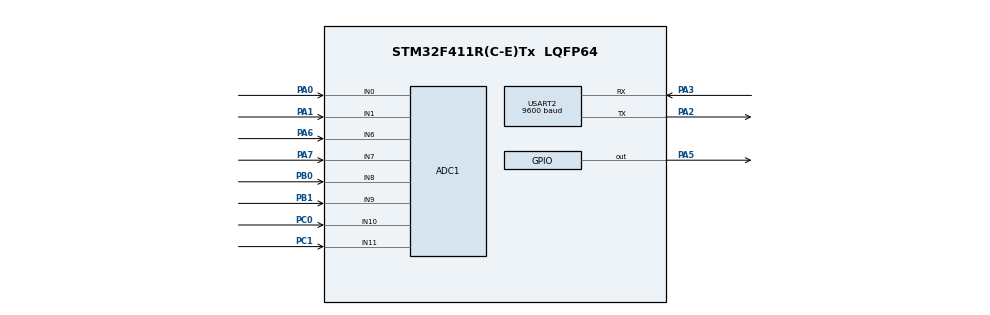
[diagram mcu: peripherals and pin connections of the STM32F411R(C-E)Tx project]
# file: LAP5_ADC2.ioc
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ADC1.Channel-13\#ChannelRegularConversion=ADC_CHANNEL_0
ADC1.Channel-14\#ChannelRegularConversion=ADC_CHANNEL_1
ADC1.Channel-15\#ChannelRegularConversion=ADC_CHANNEL_6
ADC1.Channel-16\#ChannelRegularConversion=ADC_CHANNEL_7
ADC1.Channel-17\#ChannelRegularConversion=ADC_CHANNEL_8
ADC1.Channel-18\#ChannelRegularConversion=ADC_CHANNEL_9
ADC1.Channel-19\#ChannelRegularConversion=ADC_CHANNEL_10
ADC1.Channel-20\#ChannelRegularConversion=ADC_CHANNEL_11
ADC1.ContinuousConvMode=ENABLE
ADC1.DMAContinuousRequests=ENABLE
ADC1.NbrOfConversion=8
ADC1.NbrOfConversionFlag=1
ADC1.Rank-13\#ChannelRegularConversion=1
ADC1.Rank-14\#ChannelRegularConversion=2
ADC1.Rank-15\#ChannelRegularConversion=3
ADC1.Rank-16\#ChannelRegularConversion=4
ADC1.Rank-17\#ChannelRegularConversion=5
ADC1.Rank-18\#ChannelRegularConversion=6
ADC1.Rank-19\#ChannelRegularConversion=7
ADC1.Rank-20\#ChannelRegularConversion=8
ADC1.SamplingTime-13\#ChannelRegularConversion=ADC_SAMPLETIME_3CYCLES
ADC1.SamplingTime-14\#ChannelRegularConversion=ADC_SAMPLETIME_3CYCLES
ADC1.SamplingTime-15\#ChannelRegularConversion=ADC_SAMPLETIME_3CYCLES
ADC1.SamplingTime-16\#ChannelRegularConversion=ADC_SAMPLETIME_3CYCLES
ADC1.SamplingTime-17\#ChannelRegularConversion=ADC_SAMPLETIME_3CYCLES
ADC1.SamplingTime-18\#ChannelRegularConversion=ADC_SAMPLETIME_3CYCLES
ADC1.SamplingTime-19\#ChannelRegularConversion=ADC_SAMPLETIME_3CYCLES
ADC1.SamplingTime-20\#ChannelRegularConversion=ADC_SAMPLETIME_3CYCLES
ADC1.master=1
Dma.ADC1.0.Direction=DMA_PERIPH_TO_MEMORY
Dma.ADC1.0.FIFOMode=DMA_FIFOMODE_DISABLE
Dma.ADC1.0.Instance=DMA2_Stream0
Dma.ADC1.0.MemDataAlignment=DMA_MDATAALIGN_WORD
Dma.ADC1.0.MemInc=DMA_MINC_ENABLE
Dma.ADC1.0.Mode=DMA_CIRCULAR
Dma.ADC1.0.PeriphDataAlignment=DMA_PDATAALIGN_WORD
Dma.ADC1.0.PeriphInc=DMA_PINC_DISABLE
Dma.ADC1.0.Priority=DMA_PRIORITY_LOW
Dma.Request0=ADC1
Mcu.Family=STM32F4
Mcu.Name=STM32F411R(C-E)Tx
Mcu.Package=LQFP64
NVIC.DMA2_Stream0_IRQn=true\:0\:0\:false\:false\:true\:false\:true
NVIC.PriorityGroup=NVIC_PRIORITYGROUP_2
PA0-WKUP.Signal=ADCx_IN0
PA1.Signal=ADCx_IN1
PA2.Mode=Asynchronous
PA2.Signal=USART2_TX
PA3.Mode=Asynchronous
PA3.Signal=USART2_RX
PA5.Signal=GPIO_Output
PA6.Signal=ADCx_IN6
PA7.Signal=ADCx_IN7
PB0.Signal=ADCx_IN8
PB1.Signal=ADCx_IN9
PC0.Signal=ADCx_IN10
PC1.Signal=ADCx_IN11
ProjectManager.HeapSize=0x200
ProjectManager.StackSize=0x400
ProjectManager.TargetToolchain=MDK-ARM V5.27
RCC.48MHZClocksFreq_Value=38400000
RCC.AHBCLKDivider=RCC_SYSCLK_DIV16
RCC.AHBFreq_Value=4800000
RCC.APB1CLKDivider=RCC_HCLK_DIV2
RCC.APB1Freq_Value=2400000
RCC.APB1TimFreq_Value=4800000
RCC.APB2Freq_Value=4800000
RCC.APB2TimFreq_Value=4800000
RCC.CortexFreq_Value=600000
RCC.Cortex_Div=SYSTICK_CLKSOURCE_HCLK_DIV8
RCC.FLatency-AdvancedSettings=FLASH_LATENCY_0
RCC.HCLKFreq_Value=4800000
RCC.HSE_VALUE=8000000
RCC.HSI_VALUE=16000000
RCC.LSE_VALUE=32768
RCC.PLLM=10
RCC.PLLN=96
RCC.SYSCLKFreq_VALUE=76800000
RCC.SYSCLKSource=RCC_SYSCLKSOURCE_PLLCLK
RCC.VCOOutputFreq_Value=153600000
SH.ADCx_IN0.0=ADC1_IN0,IN0
SH.ADCx_IN1.0=ADC1_IN1,IN1
SH.ADCx_IN10.0=ADC1_IN10,IN10
SH.ADCx_IN11.0=ADC1_IN11,IN11
SH.ADCx_IN6.0=ADC1_IN6,IN6
SH.ADCx_IN7.0=ADC1_IN7,IN7
SH.ADCx_IN8.0=ADC1_IN8,IN8
SH.ADCx_IN9.0=ADC1_IN9,IN9
USART2.BaudRate=9600
USART2.VirtualMode=VM_ASYNC
board=NUCLEO-F411RE

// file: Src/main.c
/* USER CODE BEGIN Header */
/**
  ******************************************************************************
  * @file           : main.c
  * @brief          : Main program body
  ******************************************************************************
  * @attention
  *
  * <h2><center>&copy; Copyright (c) 2020 STMicroelectronics.
  * All rights reserved.</center></h2>
  *
  * This software component is licensed by ST under BSD 3-Clause license,
  * the "License"; You may not use this file except in compliance with the
  * License. You may obtain a copy of the License at:
  *                        opensource.org/licenses/BSD-3-Clause
  *
  ******************************************************************************
  */
/* USER CODE END Header */

#include "main.h"
#include "adc.h"
#include "dma.h"
#include "usart.h"
#include "gpio.h"

/* USER CODE BEGIN Includes */
#include "string.h"
#include "stdio.h"
#include "stdbool.h"
/* USER CODE END Includes */

/* USER CODE BEGIN PV */
uint32_t adc_val[8];
char str[20];
char str2[20];
bool readpin;
/* USER CODE END PV */

void SystemClock_Config(void);
/* USER CODE BEGIN PFP */
void displayValue(uint32_t, int ,char str2[]);
void uart_send_msg(char str[]);
/* USER CODE END PFP */

int main(void)
{

  /* MCU Configuration--------------------------------------------------------*/

  /* Reset of all peripherals, Initializes the Flash interface and the Systick. */
  HAL_Init();

  /* Configure the system clock */
  SystemClock_Config();

  /* Initialize all configured peripherals */
  MX_GPIO_Init();
  MX_DMA_Init();
  MX_ADC1_Init();
  MX_USART2_UART_Init();
  /* USER CODE BEGIN 2 */
	HAL_ADC_Start_DMA(&hadc1, adc_val, 8);
  /* USER CODE END 2 */

  /* Infinite loop */
  while (1)
  {

    /* USER CODE BEGIN 3 */
		displayValue(adc_val[0], 0,"v LDR");
		HAL_Delay(125);
		displayValue(adc_val[1], 1,"v LDR");
		HAL_Delay(125);
		displayValue(adc_val[2], 2,"v LDR");
		HAL_Delay(125);
		displayValue(adc_val[3], 3,"v Potentiometer");
		HAL_Delay(125);
		displayValue(adc_val[4], 4,"v Potentiometer");
		HAL_Delay(125);
		displayValue(adc_val[5], 5,"v Potentiometer");
		HAL_Delay(125);
		displayValue(adc_val[6], 6,"v Potentiometer");
		HAL_Delay(125);
		displayValue(adc_val[7], 7,"v LDR");
		HAL_Delay(125);
  }
  /* USER CODE END 3 */
}

void SystemClock_Config(void)
{
  RCC_OscInitTypeDef RCC_OscInitStruct = {0};
  RCC_ClkInitTypeDef RCC_ClkInitStruct = {0};

  /** Configure the main internal regulator output voltage
  */
  __HAL_RCC_PWR_CLK_ENABLE();
  __HAL_PWR_VOLTAGESCALING_CONFIG(PWR_REGULATOR_VOLTAGE_SCALE1);
  /** Initializes the CPU, AHB and APB busses clocks
  */
  RCC_OscInitStruct.OscillatorType = RCC_OSCILLATORTYPE_HSI;
  RCC_OscInitStruct.HSIState = RCC_HSI_ON;
  RCC_OscInitStruct.HSICalibrationValue = RCC_HSICALIBRATION_DEFAULT;
  RCC_OscInitStruct.PLL.PLLState = RCC_PLL_ON;
  RCC_OscInitStruct.PLL.PLLSource = RCC_PLLSOURCE_HSI;
  RCC_OscInitStruct.PLL.PLLM = 8;
  RCC_OscInitStruct.PLL.PLLN = 100;
  RCC_OscInitStruct.PLL.PLLP = RCC_PLLP_DIV2;
  RCC_OscInitStruct.PLL.PLLQ = 4;
  if (HAL_RCC_OscConfig(&RCC_OscInitStruct) != HAL_OK)
  {
    Error_Handler();
  }
  /** Initializes the CPU, AHB and APB busses clocks
  */
  RCC_ClkInitStruct.ClockType = RCC_CLOCKTYPE_HCLK|RCC_CLOCKTYPE_SYSCLK
                              |RCC_CLOCKTYPE_PCLK1|RCC_CLOCKTYPE_PCLK2;
  RCC_ClkInitStruct.SYSCLKSource = RCC_SYSCLKSOURCE_PLLCLK;
  RCC_ClkInitStruct.AHBCLKDivider = RCC_SYSCLK_DIV1;
  RCC_ClkInitStruct.APB1CLKDivider = RCC_HCLK_DIV2;
  RCC_ClkInitStruct.APB2CLKDivider = RCC_HCLK_DIV1;

  if (HAL_RCC_ClockConfig(&RCC_ClkInitStruct, FLASH_LATENCY_3) != HAL_OK)
  {
    Error_Handler();
  }
}

/* USER CODE BEGIN 4 */
void displayValue(uint32_t adc_val, int i,char str2[])
{
	char vin[10],si[4];
	float voltage = (adc_val*3.3)/4096;
	sprintf(str, "Ox%010X", adc_val);
	sprintf(vin, "%.2f", voltage);
	sprintf(si,"%i",i);
	HAL_UART_Transmit(&huart2, (uint8_t*)"adc_channel ", 12,1000);
	HAL_UART_Transmit(&huart2, (uint8_t*)si, strlen(si), 1000);
	HAL_UART_Transmit(&huart2, (uint8_t*)" => ", 4,1000);
	HAL_UART_Transmit(&huart2, (uint8_t*)str, strlen(str),1000);
	HAL_UART_Transmit(&huart2, (uint8_t*)" vin => ", 8,1000);
	HAL_UART_Transmit(&huart2, (uint8_t*)vin, strlen(vin),1000);
	HAL_UART_Transmit(&huart2, (uint8_t*)str2, strlen(str2),1000);
	HAL_UART_Transmit(&huart2, (uint8_t*)"\n\r", 4,1000);

	// uart_send_msg(str);
	// uart_send_msg(&vin);
}
void HAL_ADC_ConvHalfCpltCallback(ADC_HandleTypeDef* hadc1)
{
	//HAL_UART_Transmit(&huart2, (uint8_t*)"HALF", 4, 100);
	HAL_GPIO_WritePin(GPIOA, GPIO_PIN_5, GPIO_PIN_SET);

	readpin = HAL_GPIO_ReadPin(GPIOA, GPIO_PIN_5);
}

void HAL_ADC_ConvCpltCallback(ADC_HandleTypeDef* hadc1)
{
	//HAL_UART_Transmit(&huart2, (uint8_t*)"FULL", 4, 100);
  HAL_GPIO_WritePin(GPIOA, GPIO_PIN_5, GPIO_PIN_RESET);

	readpin = HAL_GPIO_ReadPin(GPIOA, GPIO_PIN_5);
}

void uart_send_msg(char str[])
{
	while(__HAL_UART_GET_FLAG(&huart2, UART_FLAG_TC) == RESET){}
	HAL_UART_Transmit(&huart2, (uint8_t*)str, strlen(str),1000);
	HAL_Delay(100);
}
/* USER CODE END 4 */

void Error_Handler(void)
{
}

/************************ (C) COPYRIGHT STMicroelectronics *****END OF FILE****/
